VERSION 5.7 ;
  NOWIREEXTENSIONATPIN ON ;
  DIVIDERCHAR "/" ;
  BUSBITCHARS "[]" ;
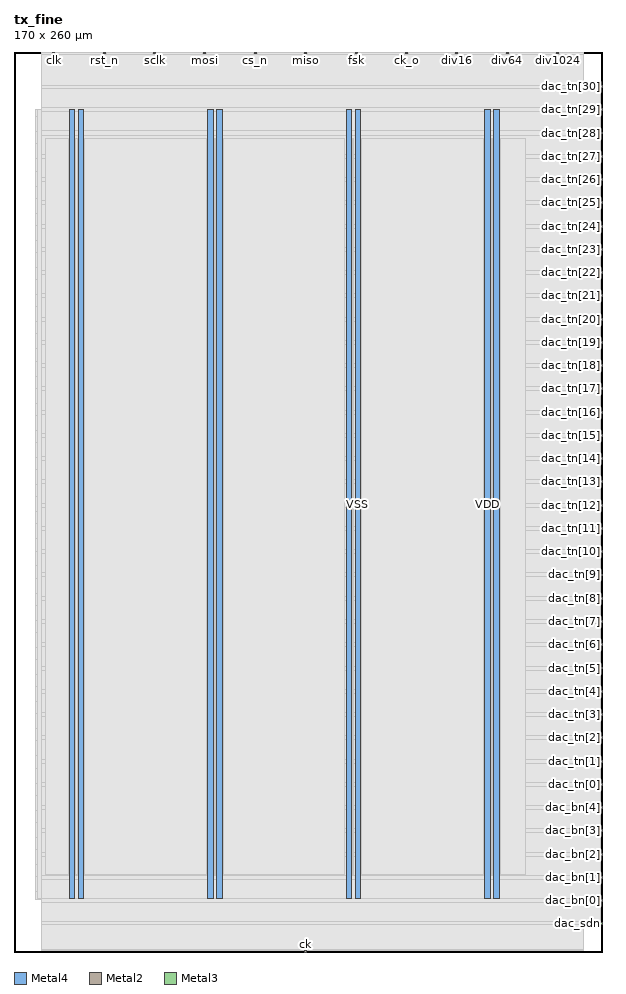
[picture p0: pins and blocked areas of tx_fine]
MACRO tx_fine
  CLASS BLOCK ;
  FOREIGN tx_fine ;
  ORIGIN 0.000 0.000 ;
  SIZE 170.000 BY 260.000 ;
  PIN VDD
    DIRECTION INOUT ;
    USE POWER ;
    PORT
      LAYER Metal4 ;
        RECT 15.920 15.380 17.520 243.340 ;
    END
    PORT
      LAYER Metal4 ;
        RECT 55.920 15.380 57.520 243.340 ;
    END
    PORT
      LAYER Metal4 ;
        RECT 95.920 15.380 97.520 243.340 ;
    END
    PORT
      LAYER Metal4 ;
        RECT 135.920 15.380 137.520 243.340 ;
    END
  END VDD
  PIN VSS
    DIRECTION INOUT ;
    USE GROUND ;
    PORT
      LAYER Metal4 ;
        RECT 18.520 15.380 20.120 243.340 ;
    END
    PORT
      LAYER Metal4 ;
        RECT 58.520 15.380 60.120 243.340 ;
    END
    PORT
      LAYER Metal4 ;
        RECT 98.520 15.380 100.120 243.340 ;
    END
    PORT
      LAYER Metal4 ;
        RECT 138.520 15.380 140.120 243.340 ;
    END
  END VSS
  PIN ck
    DIRECTION INPUT ;
    USE SIGNAL ;
    ANTENNAGATEAREA 9.476000 ;
    ANTENNADIFFAREA 0.820800 ;
    PORT
      LAYER Metal2 ;
        RECT 84.000 0.000 84.560 0.560 ;
    END
  END ck
  PIN ck_o
    DIRECTION OUTPUT ;
    USE SIGNAL ;
    ANTENNADIFFAREA 0.897600 ;
    PORT
      LAYER Metal2 ;
        RECT 113.120 259.440 113.680 260.000 ;
    END
  END ck_o
  PIN clk
    DIRECTION INPUT ;
    USE SIGNAL ;
    ANTENNAGATEAREA 4.738000 ;
    ANTENNADIFFAREA 0.410400 ;
    PORT
      LAYER Metal2 ;
        RECT 11.200 259.440 11.760 260.000 ;
    END
  END clk
  PIN cs_n
    DIRECTION INPUT ;
    USE SIGNAL ;
    ANTENNAGATEAREA 0.498500 ;
    ANTENNADIFFAREA 0.410400 ;
    PORT
      LAYER Metal2 ;
        RECT 69.440 259.440 70.000 260.000 ;
    END
  END cs_n
  PIN dac_bn[0]
    DIRECTION OUTPUT ;
    USE SIGNAL ;
    ANTENNADIFFAREA 0.897600 ;
    PORT
      LAYER Metal3 ;
        RECT 169.440 14.560 170.000 15.120 ;
    END
  END dac_bn[0]
  PIN dac_bn[1]
    DIRECTION OUTPUT ;
    USE SIGNAL ;
    ANTENNADIFFAREA 0.897600 ;
    PORT
      LAYER Metal3 ;
        RECT 169.440 21.280 170.000 21.840 ;
    END
  END dac_bn[1]
  PIN dac_bn[2]
    DIRECTION OUTPUT ;
    USE SIGNAL ;
    ANTENNADIFFAREA 0.897600 ;
    PORT
      LAYER Metal3 ;
        RECT 169.440 28.000 170.000 28.560 ;
    END
  END dac_bn[2]
  PIN dac_bn[3]
    DIRECTION OUTPUT ;
    USE SIGNAL ;
    ANTENNADIFFAREA 0.897600 ;
    PORT
      LAYER Metal3 ;
        RECT 169.440 34.720 170.000 35.280 ;
    END
  END dac_bn[3]
  PIN dac_bn[4]
    DIRECTION OUTPUT ;
    USE SIGNAL ;
    ANTENNADIFFAREA 0.897600 ;
    PORT
      LAYER Metal3 ;
        RECT 169.440 41.440 170.000 42.000 ;
    END
  END dac_bn[4]
  PIN dac_sdn
    DIRECTION OUTPUT ;
    USE SIGNAL ;
    ANTENNADIFFAREA 0.897600 ;
    PORT
      LAYER Metal3 ;
        RECT 169.440 7.840 170.000 8.400 ;
    END
  END dac_sdn
  PIN dac_tn[0]
    DIRECTION OUTPUT ;
    USE SIGNAL ;
    ANTENNADIFFAREA 0.897600 ;
    PORT
      LAYER Metal3 ;
        RECT 169.440 48.160 170.000 48.720 ;
    END
  END dac_tn[0]
  PIN dac_tn[10]
    DIRECTION OUTPUT ;
    USE SIGNAL ;
    ANTENNADIFFAREA 0.897600 ;
    PORT
      LAYER Metal3 ;
        RECT 169.440 115.360 170.000 115.920 ;
    END
  END dac_tn[10]
  PIN dac_tn[11]
    DIRECTION OUTPUT ;
    USE SIGNAL ;
    ANTENNADIFFAREA 0.897600 ;
    PORT
      LAYER Metal3 ;
        RECT 169.440 122.080 170.000 122.640 ;
    END
  END dac_tn[11]
  PIN dac_tn[12]
    DIRECTION OUTPUT ;
    USE SIGNAL ;
    ANTENNADIFFAREA 0.897600 ;
    PORT
      LAYER Metal3 ;
        RECT 169.440 128.800 170.000 129.360 ;
    END
  END dac_tn[12]
  PIN dac_tn[13]
    DIRECTION OUTPUT ;
    USE SIGNAL ;
    ANTENNADIFFAREA 0.897600 ;
    PORT
      LAYER Metal3 ;
        RECT 169.440 135.520 170.000 136.080 ;
    END
  END dac_tn[13]
  PIN dac_tn[14]
    DIRECTION OUTPUT ;
    USE SIGNAL ;
    ANTENNADIFFAREA 0.897600 ;
    PORT
      LAYER Metal3 ;
        RECT 169.440 142.240 170.000 142.800 ;
    END
  END dac_tn[14]
  PIN dac_tn[15]
    DIRECTION OUTPUT ;
    USE SIGNAL ;
    ANTENNADIFFAREA 0.897600 ;
    PORT
      LAYER Metal3 ;
        RECT 169.440 148.960 170.000 149.520 ;
    END
  END dac_tn[15]
  PIN dac_tn[16]
    DIRECTION OUTPUT ;
    USE SIGNAL ;
    ANTENNADIFFAREA 0.897600 ;
    PORT
      LAYER Metal3 ;
        RECT 169.440 155.680 170.000 156.240 ;
    END
  END dac_tn[16]
  PIN dac_tn[17]
    DIRECTION OUTPUT ;
    USE SIGNAL ;
    ANTENNADIFFAREA 0.897600 ;
    PORT
      LAYER Metal3 ;
        RECT 169.440 162.400 170.000 162.960 ;
    END
  END dac_tn[17]
  PIN dac_tn[18]
    DIRECTION OUTPUT ;
    USE SIGNAL ;
    ANTENNADIFFAREA 0.897600 ;
    PORT
      LAYER Metal3 ;
        RECT 169.440 169.120 170.000 169.680 ;
    END
  END dac_tn[18]
  PIN dac_tn[19]
    DIRECTION OUTPUT ;
    USE SIGNAL ;
    ANTENNADIFFAREA 0.897600 ;
    PORT
      LAYER Metal3 ;
        RECT 169.440 175.840 170.000 176.400 ;
    END
  END dac_tn[19]
  PIN dac_tn[1]
    DIRECTION OUTPUT ;
    USE SIGNAL ;
    ANTENNADIFFAREA 0.897600 ;
    PORT
      LAYER Metal3 ;
        RECT 169.440 54.880 170.000 55.440 ;
    END
  END dac_tn[1]
  PIN dac_tn[20]
    DIRECTION OUTPUT ;
    USE SIGNAL ;
    ANTENNADIFFAREA 0.897600 ;
    PORT
      LAYER Metal3 ;
        RECT 169.440 182.560 170.000 183.120 ;
    END
  END dac_tn[20]
  PIN dac_tn[21]
    DIRECTION OUTPUT ;
    USE SIGNAL ;
    ANTENNADIFFAREA 0.897600 ;
    PORT
      LAYER Metal3 ;
        RECT 169.440 189.280 170.000 189.840 ;
    END
  END dac_tn[21]
  PIN dac_tn[22]
    DIRECTION OUTPUT ;
    USE SIGNAL ;
    ANTENNADIFFAREA 0.897600 ;
    PORT
      LAYER Metal3 ;
        RECT 169.440 196.000 170.000 196.560 ;
    END
  END dac_tn[22]
  PIN dac_tn[23]
    DIRECTION OUTPUT ;
    USE SIGNAL ;
    ANTENNADIFFAREA 0.897600 ;
    PORT
      LAYER Metal3 ;
        RECT 169.440 202.720 170.000 203.280 ;
    END
  END dac_tn[23]
  PIN dac_tn[24]
    DIRECTION OUTPUT ;
    USE SIGNAL ;
    ANTENNADIFFAREA 0.897600 ;
    PORT
      LAYER Metal3 ;
        RECT 169.440 209.440 170.000 210.000 ;
    END
  END dac_tn[24]
  PIN dac_tn[25]
    DIRECTION OUTPUT ;
    USE SIGNAL ;
    ANTENNADIFFAREA 0.897600 ;
    PORT
      LAYER Metal3 ;
        RECT 169.440 216.160 170.000 216.720 ;
    END
  END dac_tn[25]
  PIN dac_tn[26]
    DIRECTION OUTPUT ;
    USE SIGNAL ;
    ANTENNADIFFAREA 0.897600 ;
    PORT
      LAYER Metal3 ;
        RECT 169.440 222.880 170.000 223.440 ;
    END
  END dac_tn[26]
  PIN dac_tn[27]
    DIRECTION OUTPUT ;
    USE SIGNAL ;
    ANTENNADIFFAREA 0.897600 ;
    PORT
      LAYER Metal3 ;
        RECT 169.440 229.600 170.000 230.160 ;
    END
  END dac_tn[27]
  PIN dac_tn[28]
    DIRECTION OUTPUT ;
    USE SIGNAL ;
    ANTENNADIFFAREA 0.897600 ;
    PORT
      LAYER Metal3 ;
        RECT 169.440 236.320 170.000 236.880 ;
    END
  END dac_tn[28]
  PIN dac_tn[29]
    DIRECTION OUTPUT ;
    USE SIGNAL ;
    ANTENNADIFFAREA 0.897600 ;
    PORT
      LAYER Metal3 ;
        RECT 169.440 243.040 170.000 243.600 ;
    END
  END dac_tn[29]
  PIN dac_tn[2]
    DIRECTION OUTPUT ;
    USE SIGNAL ;
    ANTENNADIFFAREA 0.897600 ;
    PORT
      LAYER Metal3 ;
        RECT 169.440 61.600 170.000 62.160 ;
    END
  END dac_tn[2]
  PIN dac_tn[30]
    DIRECTION OUTPUT ;
    USE SIGNAL ;
    ANTENNADIFFAREA 0.897600 ;
    PORT
      LAYER Metal3 ;
        RECT 169.440 249.760 170.000 250.320 ;
    END
  END dac_tn[30]
  PIN dac_tn[3]
    DIRECTION OUTPUT ;
    USE SIGNAL ;
    ANTENNADIFFAREA 0.897600 ;
    PORT
      LAYER Metal3 ;
        RECT 169.440 68.320 170.000 68.880 ;
    END
  END dac_tn[3]
  PIN dac_tn[4]
    DIRECTION OUTPUT ;
    USE SIGNAL ;
    ANTENNADIFFAREA 0.897600 ;
    PORT
      LAYER Metal3 ;
        RECT 169.440 75.040 170.000 75.600 ;
    END
  END dac_tn[4]
  PIN dac_tn[5]
    DIRECTION OUTPUT ;
    USE SIGNAL ;
    ANTENNADIFFAREA 0.897600 ;
    PORT
      LAYER Metal3 ;
        RECT 169.440 81.760 170.000 82.320 ;
    END
  END dac_tn[5]
  PIN dac_tn[6]
    DIRECTION OUTPUT ;
    USE SIGNAL ;
    ANTENNADIFFAREA 0.897600 ;
    PORT
      LAYER Metal3 ;
        RECT 169.440 88.480 170.000 89.040 ;
    END
  END dac_tn[6]
  PIN dac_tn[7]
    DIRECTION OUTPUT ;
    USE SIGNAL ;
    ANTENNADIFFAREA 0.897600 ;
    PORT
      LAYER Metal3 ;
        RECT 169.440 95.200 170.000 95.760 ;
    END
  END dac_tn[7]
  PIN dac_tn[8]
    DIRECTION OUTPUT ;
    USE SIGNAL ;
    ANTENNADIFFAREA 0.897600 ;
    PORT
      LAYER Metal3 ;
        RECT 169.440 101.920 170.000 102.480 ;
    END
  END dac_tn[8]
  PIN dac_tn[9]
    DIRECTION OUTPUT ;
    USE SIGNAL ;
    ANTENNADIFFAREA 0.897600 ;
    PORT
      LAYER Metal3 ;
        RECT 169.440 108.640 170.000 109.200 ;
    END
  END dac_tn[9]
  PIN div1024
    DIRECTION OUTPUT ;
    USE SIGNAL ;
    ANTENNADIFFAREA 0.897600 ;
    PORT
      LAYER Metal2 ;
        RECT 156.800 259.440 157.360 260.000 ;
    END
  END div1024
  PIN div16
    DIRECTION OUTPUT ;
    USE SIGNAL ;
    ANTENNADIFFAREA 0.897600 ;
    PORT
      LAYER Metal2 ;
        RECT 127.680 259.440 128.240 260.000 ;
    END
  END div16
  PIN div64
    DIRECTION OUTPUT ;
    USE SIGNAL ;
    ANTENNADIFFAREA 0.897600 ;
    PORT
      LAYER Metal2 ;
        RECT 142.240 259.440 142.800 260.000 ;
    END
  END div64
  PIN fsk
    DIRECTION INPUT ;
    USE SIGNAL ;
    ANTENNAGATEAREA 0.498500 ;
    ANTENNADIFFAREA 0.410400 ;
    PORT
      LAYER Metal2 ;
        RECT 98.560 259.440 99.120 260.000 ;
    END
  END fsk
  PIN miso
    DIRECTION OUTPUT ;
    USE SIGNAL ;
    ANTENNADIFFAREA 0.897600 ;
    PORT
      LAYER Metal2 ;
        RECT 84.000 259.440 84.560 260.000 ;
    END
  END miso
  PIN mosi
    DIRECTION INPUT ;
    USE SIGNAL ;
    ANTENNAGATEAREA 0.498500 ;
    ANTENNADIFFAREA 0.410400 ;
    PORT
      LAYER Metal2 ;
        RECT 54.880 259.440 55.440 260.000 ;
    END
  END mosi
  PIN rst_n
    DIRECTION INPUT ;
    USE SIGNAL ;
    ANTENNAGATEAREA 1.102000 ;
    ANTENNADIFFAREA 0.410400 ;
    PORT
      LAYER Metal2 ;
        RECT 25.760 259.440 26.320 260.000 ;
    END
  END rst_n
  PIN sclk
    DIRECTION INPUT ;
    USE SIGNAL ;
    ANTENNAGATEAREA 0.498500 ;
    ANTENNADIFFAREA 0.410400 ;
    PORT
      LAYER Metal2 ;
        RECT 40.320 259.440 40.880 260.000 ;
    END
  END sclk
  OBS
      LAYER Pwell ;
        RECT 6.290 241.280 163.390 243.470 ;
      LAYER Nwell ;
        RECT 6.290 236.960 163.390 241.280 ;
      LAYER Pwell ;
        RECT 6.290 233.440 163.390 236.960 ;
      LAYER Nwell ;
        RECT 6.290 229.120 163.390 233.440 ;
      LAYER Pwell ;
        RECT 6.290 225.600 163.390 229.120 ;
      LAYER Nwell ;
        RECT 6.290 221.280 163.390 225.600 ;
      LAYER Pwell ;
        RECT 6.290 217.760 163.390 221.280 ;
      LAYER Nwell ;
        RECT 6.290 213.440 163.390 217.760 ;
      LAYER Pwell ;
        RECT 6.290 209.920 163.390 213.440 ;
      LAYER Nwell ;
        RECT 6.290 205.600 163.390 209.920 ;
      LAYER Pwell ;
        RECT 6.290 202.080 163.390 205.600 ;
      LAYER Nwell ;
        RECT 6.290 197.760 163.390 202.080 ;
      LAYER Pwell ;
        RECT 6.290 194.240 163.390 197.760 ;
      LAYER Nwell ;
        RECT 6.290 189.920 163.390 194.240 ;
      LAYER Pwell ;
        RECT 6.290 186.400 163.390 189.920 ;
      LAYER Nwell ;
        RECT 6.290 182.080 163.390 186.400 ;
      LAYER Pwell ;
        RECT 6.290 178.560 163.390 182.080 ;
      LAYER Nwell ;
        RECT 6.290 174.240 163.390 178.560 ;
      LAYER Pwell ;
        RECT 6.290 170.720 163.390 174.240 ;
      LAYER Nwell ;
        RECT 6.290 166.400 163.390 170.720 ;
      LAYER Pwell ;
        RECT 6.290 162.880 163.390 166.400 ;
      LAYER Nwell ;
        RECT 6.290 158.560 163.390 162.880 ;
      LAYER Pwell ;
        RECT 6.290 155.040 163.390 158.560 ;
      LAYER Nwell ;
        RECT 6.290 150.720 163.390 155.040 ;
      LAYER Pwell ;
        RECT 6.290 147.200 163.390 150.720 ;
      LAYER Nwell ;
        RECT 6.290 142.880 163.390 147.200 ;
      LAYER Pwell ;
        RECT 6.290 139.360 163.390 142.880 ;
      LAYER Nwell ;
        RECT 6.290 135.040 163.390 139.360 ;
      LAYER Pwell ;
        RECT 6.290 131.520 163.390 135.040 ;
      LAYER Nwell ;
        RECT 6.290 127.200 163.390 131.520 ;
      LAYER Pwell ;
        RECT 6.290 123.680 163.390 127.200 ;
      LAYER Nwell ;
        RECT 6.290 119.360 163.390 123.680 ;
      LAYER Pwell ;
        RECT 6.290 115.840 163.390 119.360 ;
      LAYER Nwell ;
        RECT 6.290 111.520 163.390 115.840 ;
      LAYER Pwell ;
        RECT 6.290 108.000 163.390 111.520 ;
      LAYER Nwell ;
        RECT 6.290 103.680 163.390 108.000 ;
      LAYER Pwell ;
        RECT 6.290 100.160 163.390 103.680 ;
      LAYER Nwell ;
        RECT 6.290 95.840 163.390 100.160 ;
      LAYER Pwell ;
        RECT 6.290 92.320 163.390 95.840 ;
      LAYER Nwell ;
        RECT 6.290 88.000 163.390 92.320 ;
      LAYER Pwell ;
        RECT 6.290 84.480 163.390 88.000 ;
      LAYER Nwell ;
        RECT 6.290 80.160 163.390 84.480 ;
      LAYER Pwell ;
        RECT 6.290 76.640 163.390 80.160 ;
      LAYER Nwell ;
        RECT 6.290 72.320 163.390 76.640 ;
      LAYER Pwell ;
        RECT 6.290 68.800 163.390 72.320 ;
      LAYER Nwell ;
        RECT 6.290 64.480 163.390 68.800 ;
      LAYER Pwell ;
        RECT 6.290 60.960 163.390 64.480 ;
      LAYER Nwell ;
        RECT 6.290 56.640 163.390 60.960 ;
      LAYER Pwell ;
        RECT 6.290 53.120 163.390 56.640 ;
      LAYER Nwell ;
        RECT 6.290 48.800 163.390 53.120 ;
      LAYER Pwell ;
        RECT 6.290 45.280 163.390 48.800 ;
      LAYER Nwell ;
        RECT 6.290 40.960 163.390 45.280 ;
      LAYER Pwell ;
        RECT 6.290 37.440 163.390 40.960 ;
      LAYER Nwell ;
        RECT 6.290 33.120 163.390 37.440 ;
      LAYER Pwell ;
        RECT 6.290 29.600 163.390 33.120 ;
      LAYER Nwell ;
        RECT 6.290 25.280 163.390 29.600 ;
      LAYER Pwell ;
        RECT 6.290 21.760 163.390 25.280 ;
      LAYER Nwell ;
        RECT 6.290 17.440 163.390 21.760 ;
      LAYER Pwell ;
        RECT 6.290 15.250 163.390 17.440 ;
      LAYER Metal1 ;
        RECT 6.720 15.380 162.960 243.340 ;
      LAYER Metal2 ;
        RECT 7.980 259.140 10.900 259.860 ;
        RECT 12.060 259.140 25.460 259.860 ;
        RECT 26.620 259.140 40.020 259.860 ;
        RECT 41.180 259.140 54.580 259.860 ;
        RECT 55.740 259.140 69.140 259.860 ;
        RECT 70.300 259.140 83.700 259.860 ;
        RECT 84.860 259.140 98.260 259.860 ;
        RECT 99.420 259.140 112.820 259.860 ;
        RECT 113.980 259.140 127.380 259.860 ;
        RECT 128.540 259.140 141.940 259.860 ;
        RECT 143.100 259.140 156.500 259.860 ;
        RECT 157.660 259.140 164.500 259.860 ;
        RECT 7.980 0.860 164.500 259.140 ;
        RECT 7.980 0.560 83.700 0.860 ;
        RECT 84.860 0.560 164.500 0.860 ;
      LAYER Metal3 ;
        RECT 7.930 249.460 169.140 250.180 ;
        RECT 7.930 243.900 169.440 249.460 ;
        RECT 7.930 242.740 169.140 243.900 ;
        RECT 7.930 237.180 169.440 242.740 ;
        RECT 7.930 236.020 169.140 237.180 ;
        RECT 7.930 230.460 169.440 236.020 ;
        RECT 7.930 229.300 169.140 230.460 ;
        RECT 7.930 223.740 169.440 229.300 ;
        RECT 7.930 222.580 169.140 223.740 ;
        RECT 7.930 217.020 169.440 222.580 ;
        RECT 7.930 215.860 169.140 217.020 ;
        RECT 7.930 210.300 169.440 215.860 ;
        RECT 7.930 209.140 169.140 210.300 ;
        RECT 7.930 203.580 169.440 209.140 ;
        RECT 7.930 202.420 169.140 203.580 ;
        RECT 7.930 196.860 169.440 202.420 ;
        RECT 7.930 195.700 169.140 196.860 ;
        RECT 7.930 190.140 169.440 195.700 ;
        RECT 7.930 188.980 169.140 190.140 ;
        RECT 7.930 183.420 169.440 188.980 ;
        RECT 7.930 182.260 169.140 183.420 ;
        RECT 7.930 176.700 169.440 182.260 ;
        RECT 7.930 175.540 169.140 176.700 ;
        RECT 7.930 169.980 169.440 175.540 ;
        RECT 7.930 168.820 169.140 169.980 ;
        RECT 7.930 163.260 169.440 168.820 ;
        RECT 7.930 162.100 169.140 163.260 ;
        RECT 7.930 156.540 169.440 162.100 ;
        RECT 7.930 155.380 169.140 156.540 ;
        RECT 7.930 149.820 169.440 155.380 ;
        RECT 7.930 148.660 169.140 149.820 ;
        RECT 7.930 143.100 169.440 148.660 ;
        RECT 7.930 141.940 169.140 143.100 ;
        RECT 7.930 136.380 169.440 141.940 ;
        RECT 7.930 135.220 169.140 136.380 ;
        RECT 7.930 129.660 169.440 135.220 ;
        RECT 7.930 128.500 169.140 129.660 ;
        RECT 7.930 122.940 169.440 128.500 ;
        RECT 7.930 121.780 169.140 122.940 ;
        RECT 7.930 116.220 169.440 121.780 ;
        RECT 7.930 115.060 169.140 116.220 ;
        RECT 7.930 109.500 169.440 115.060 ;
        RECT 7.930 108.340 169.140 109.500 ;
        RECT 7.930 102.780 169.440 108.340 ;
        RECT 7.930 101.620 169.140 102.780 ;
        RECT 7.930 96.060 169.440 101.620 ;
        RECT 7.930 94.900 169.140 96.060 ;
        RECT 7.930 89.340 169.440 94.900 ;
        RECT 7.930 88.180 169.140 89.340 ;
        RECT 7.930 82.620 169.440 88.180 ;
        RECT 7.930 81.460 169.140 82.620 ;
        RECT 7.930 75.900 169.440 81.460 ;
        RECT 7.930 74.740 169.140 75.900 ;
        RECT 7.930 69.180 169.440 74.740 ;
        RECT 7.930 68.020 169.140 69.180 ;
        RECT 7.930 62.460 169.440 68.020 ;
        RECT 7.930 61.300 169.140 62.460 ;
        RECT 7.930 55.740 169.440 61.300 ;
        RECT 7.930 54.580 169.140 55.740 ;
        RECT 7.930 49.020 169.440 54.580 ;
        RECT 7.930 47.860 169.140 49.020 ;
        RECT 7.930 42.300 169.440 47.860 ;
        RECT 7.930 41.140 169.140 42.300 ;
        RECT 7.930 35.580 169.440 41.140 ;
        RECT 7.930 34.420 169.140 35.580 ;
        RECT 7.930 28.860 169.440 34.420 ;
        RECT 7.930 27.700 169.140 28.860 ;
        RECT 7.930 22.140 169.440 27.700 ;
        RECT 7.930 20.980 169.140 22.140 ;
        RECT 7.930 15.420 169.440 20.980 ;
        RECT 7.930 14.260 169.140 15.420 ;
        RECT 7.930 8.700 169.440 14.260 ;
        RECT 7.930 7.980 169.140 8.700 ;
      LAYER Metal4 ;
        RECT 9.100 22.490 15.620 235.110 ;
        RECT 17.820 22.490 18.220 235.110 ;
        RECT 20.420 22.490 55.620 235.110 ;
        RECT 57.820 22.490 58.220 235.110 ;
        RECT 60.420 22.490 95.620 235.110 ;
        RECT 97.820 22.490 98.220 235.110 ;
        RECT 100.420 22.490 135.620 235.110 ;
        RECT 137.820 22.490 138.220 235.110 ;
        RECT 140.420 22.490 147.700 235.110 ;
  END
END tx_fine
END LIBRARY

